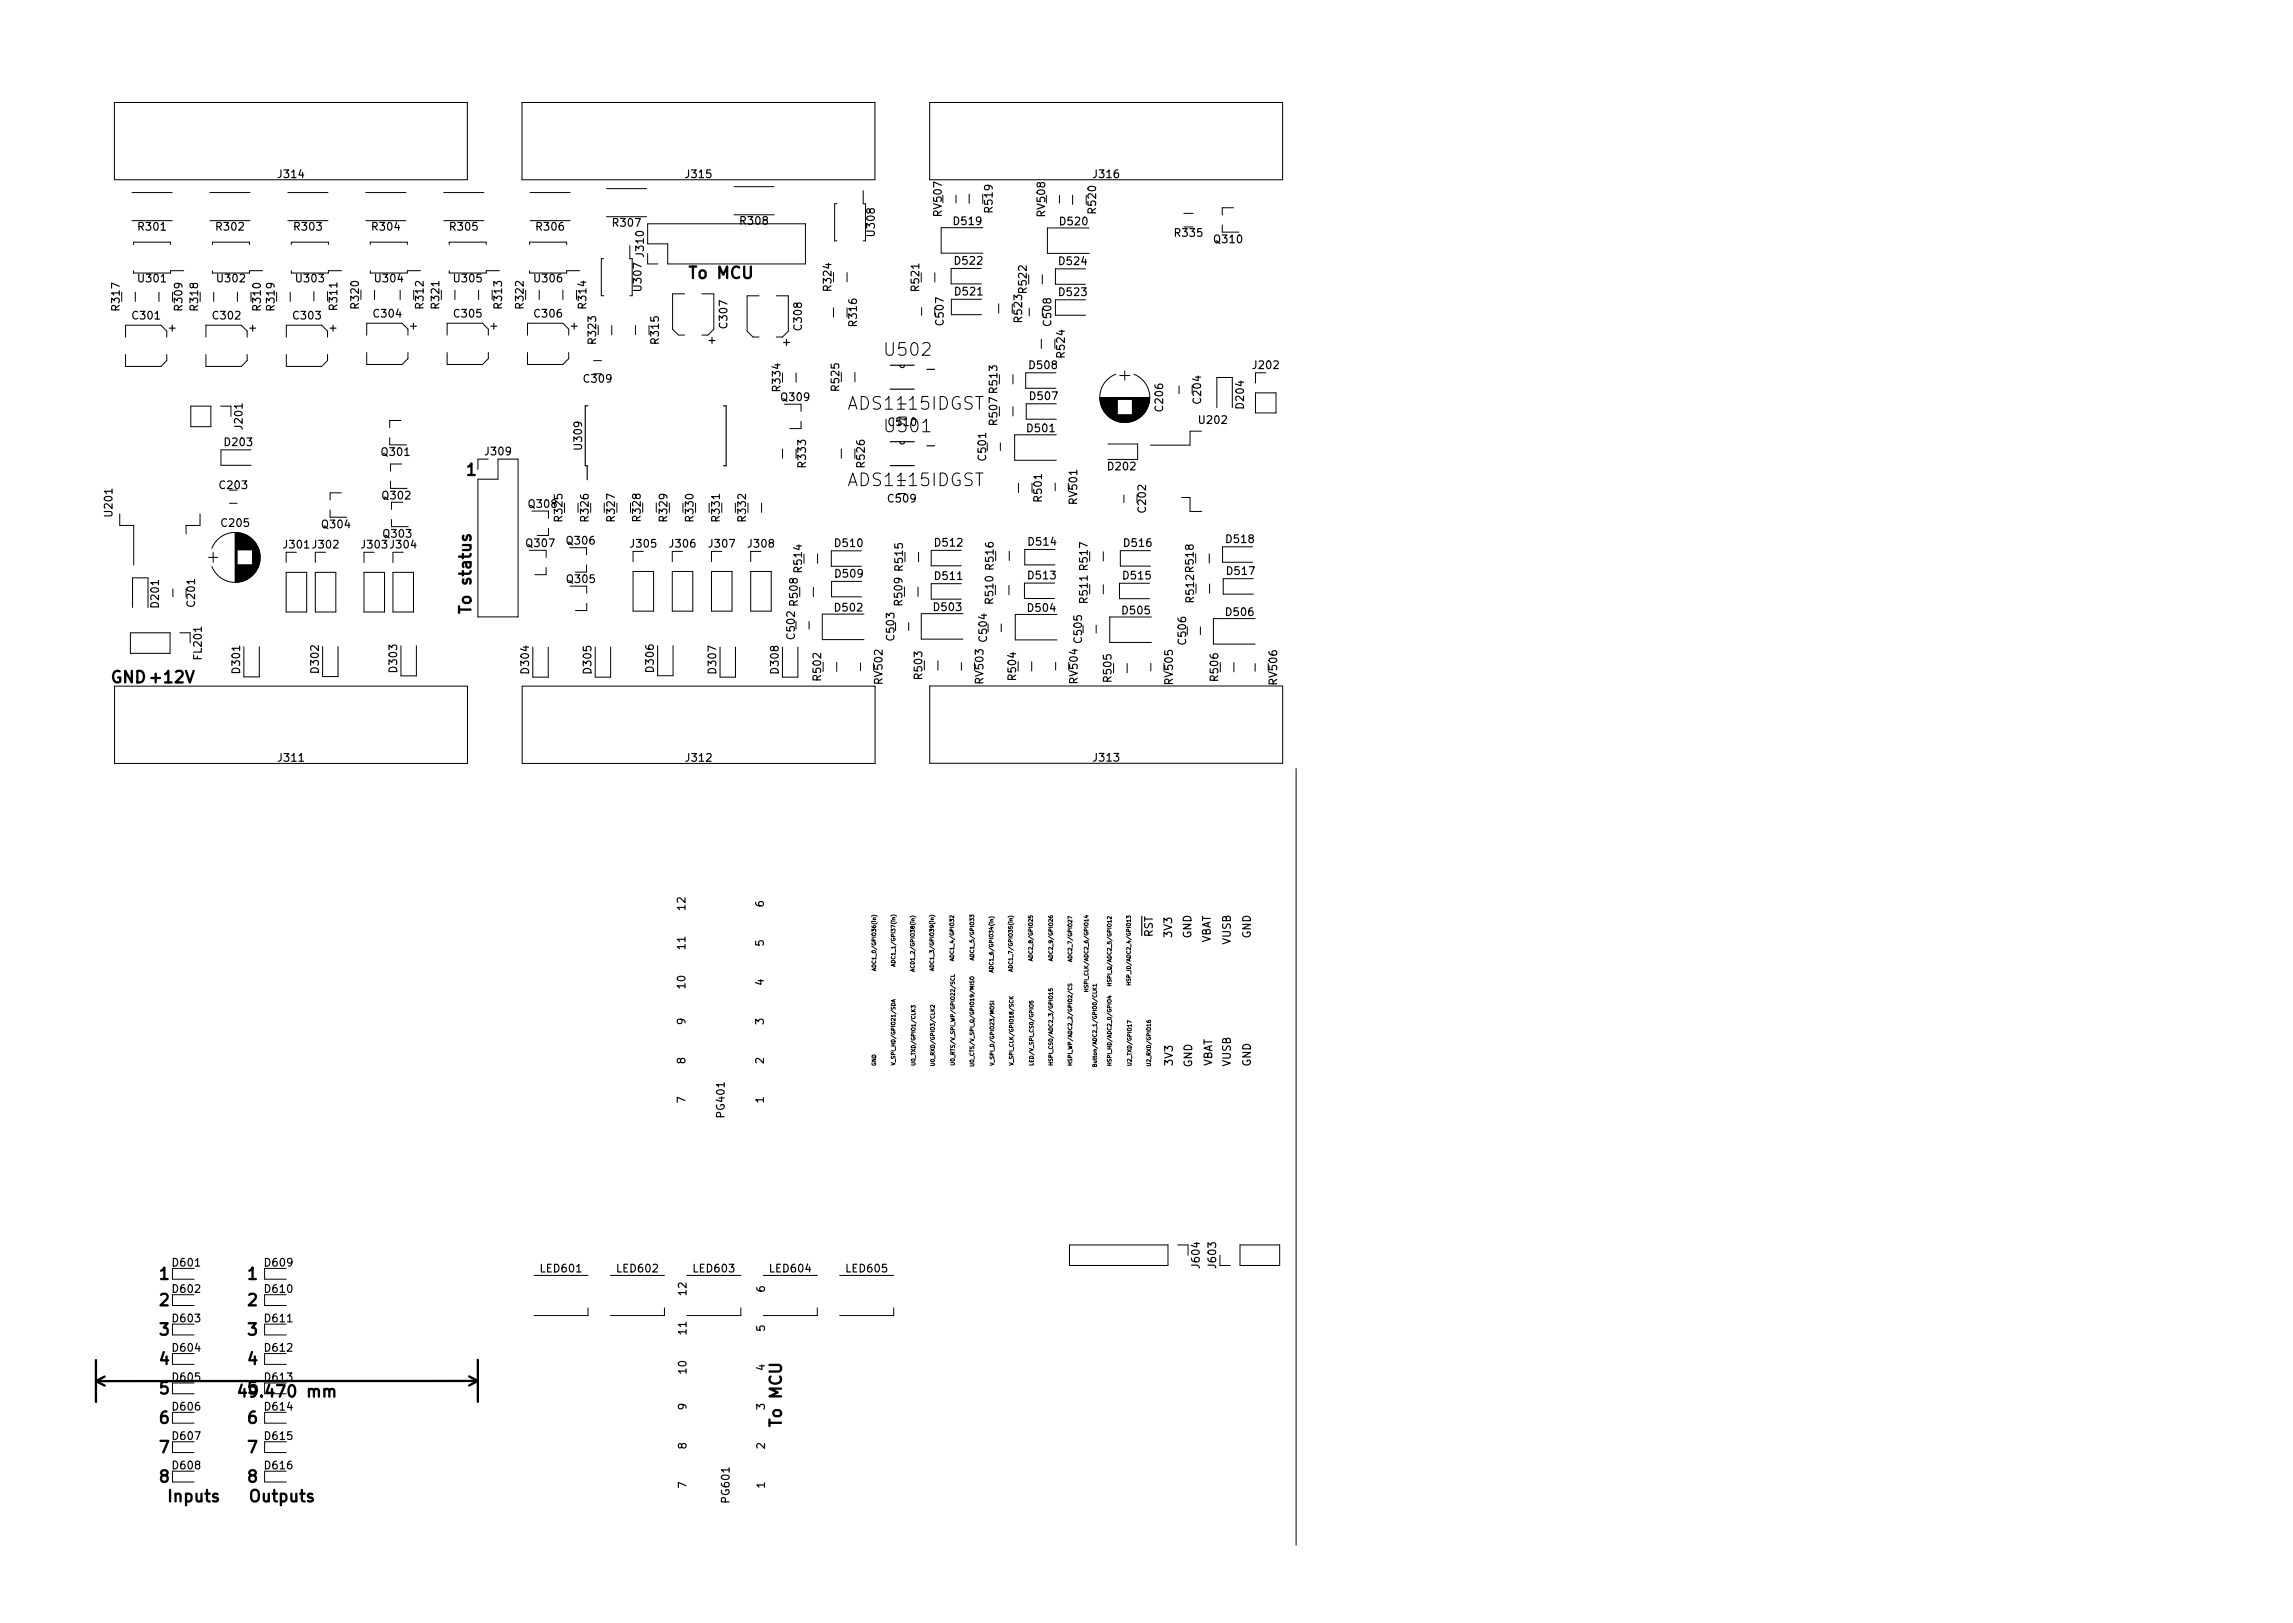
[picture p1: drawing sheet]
<svg xmlns="http://www.w3.org/2000/svg" width="297mm" height="210mm" viewBox="0 0 297 210" stroke-linecap="round" stroke-linejoin="round" font-family="sans-serif">
<defs><g id="words">
<g font-size="2.3">
<text x="114.9" y="46.1">U502</text>
<text x="110.2" y="53.1">ADS1115IDGST</text>
<text x="114.9" y="56">U501</text>
<text x="110.2" y="63">ADS1115IDGST</text>
</g>
<g font-size="2.1">
<text x="89.5" y="36.1">To MCU</text>
<text x="60.5" y="61.6">1</text>
<text x="61" y="78.9" transform="rotate(-90 61 78.9)">To status</text>
<text x="14.3" y="88.5">GND +12V</text>
<text x="20.7" y="165.8">1</text>
<text x="32.1" y="165.8">1</text>
<text x="20.7" y="173">3</text>
<text x="20.7" y="169.2">2</text>
<text x="32.1" y="173">3</text>
<text x="32.1" y="169.2">2</text>
<text x="20.7" y="176.8">4</text>
<text x="32.1" y="176.8">4</text>
<text x="20.7" y="184.4">6</text>
<text x="20.7" y="180.6">5</text>
<text x="31.8" y="181">49.470 mm</text>
<text x="32.1" y="184.4">6</text>
<text x="32.1" y="180.6">5</text>
<text x="101.2" y="184.6" transform="rotate(-90 101.2 184.6)">To MCU</text>
<text x="20.7" y="188.2">7</text>
<text x="32.1" y="188.2">7</text>
<text x="20.7" y="192">8</text>
<text x="22" y="194.6">Inputs</text>
<text x="32.1" y="192">8</text>
<text x="32.5" y="194.6">Outputs</text>
</g>
<g font-size="1.4">
<text x="36.1" y="23.1">J314</text>
<text x="88.9" y="23.1">J315</text>
<text x="141.7" y="23.1">J316</text>
<text x="18" y="29.9">R301</text>
<text x="28.1" y="29.9">R302</text>
<text x="38.2" y="29.9">R303</text>
<text x="48.3" y="29.9">R304</text>
<text x="58.4" y="29.9">R305</text>
<text x="69.6" y="29.9">R306</text>
<text x="79.5" y="29.4">R307</text>
<text x="96" y="29.1">R308</text>
<text x="122" y="27.9" transform="rotate(-90 122 27.9)">RV507</text>
<text x="123.7" y="29.1">D519</text>
<text x="128.6" y="27.4" transform="rotate(-90 128.6 27.4)">R519</text>
<text x="135.4" y="27.9" transform="rotate(-90 135.4 27.9)">RV508</text>
<text x="137.4" y="29.2">D520</text>
<text x="142" y="27.5" transform="rotate(-90 142 27.5)">R520</text>
<text x="83.4" y="33.1" transform="rotate(-90 83.4 33.1)">J310</text>
<text x="113.3" y="30.5" transform="rotate(-90 113.3 30.5)">U308</text>
<text x="123.8" y="34.3">D522</text>
<text x="137.3" y="34.3">D524</text>
<text x="152.3" y="30.7">R335</text>
<text x="157.4" y="31.5">Q310</text>
<text x="15.5" y="40.1" transform="rotate(-90 15.5 40.1)">R317</text>
<text x="17.3" y="41.4">C301</text>
<text x="18" y="36.6">U301</text>
<text x="23.6" y="40.1" transform="rotate(-90 23.6 40.1)">R309</text>
<text x="25.7" y="40.1" transform="rotate(-90 25.7 40.1)">R318</text>
<text x="27.7" y="41.4">C302</text>
<text x="28.3" y="36.6">U302</text>
<text x="33.8" y="40.1" transform="rotate(-90 33.8 40.1)">R310</text>
<text x="35.6" y="40.1" transform="rotate(-90 35.6 40.1)">R319</text>
<text x="38.1" y="41.4">C303</text>
<text x="38.5" y="36.6">U303</text>
<text x="43.7" y="40" transform="rotate(-90 43.7 40)">R311</text>
<text x="46.5" y="39.9" transform="rotate(-90 46.5 39.9)">R320</text>
<text x="48.5" y="41.1">C304</text>
<text x="48.7" y="36.6">U304</text>
<text x="54.9" y="39.9" transform="rotate(-90 54.9 39.9)">R312</text>
<text x="56.9" y="39.9" transform="rotate(-90 56.9 39.9)">R321</text>
<text x="58.9" y="41.1">C305</text>
<text x="58.9" y="36.6">U305</text>
<text x="65" y="39.9" transform="rotate(-90 65 39.9)">R313</text>
<text x="67.8" y="39.9" transform="rotate(-90 67.8 39.9)">R322</text>
<text x="69.3" y="41.1">C306</text>
<text x="69.3" y="36.6">U306</text>
<text x="75.9" y="39.9" transform="rotate(-90 75.9 39.9)">R314</text>
<text x="83.1" y="37.6" transform="rotate(-90 83.1 37.6)">U307</text>
<text x="107.7" y="37.6" transform="rotate(-90 107.7 37.6)">R324</text>
<text x="119.1" y="37.6" transform="rotate(-90 119.1 37.6)">R521</text>
<text x="123.8" y="38.3">D521</text>
<text x="132.4" y="41.6" transform="rotate(-90 132.4 41.6)">R523</text>
<text x="133" y="37.9" transform="rotate(-90 133 37.9)">R522</text>
<text x="137.3" y="38.3">D523</text>
<text x="21.9" y="42.9">+</text>
<text x="32.3" y="42.9">+</text>
<text x="42.7" y="42.9">+</text>
<text x="53.1" y="42.7">+</text>
<text x="63.6" y="42.7">+</text>
<text x="74" y="42.7">+</text>
<text x="77.2" y="44.4" transform="rotate(-90 77.2 44.4)">R323</text>
<text x="85.3" y="44.4" transform="rotate(-90 85.3 44.4)">R315</text>
<text x="92.7" y="44.5" transform="rotate(-90 92.7 44.5)">+</text>
<text x="94.2" y="42.4" transform="rotate(-90 94.2 42.4)">C307</text>
<text x="102.3" y="44.8" transform="rotate(-90 102.3 44.8)">+</text>
<text x="103.9" y="42.7" transform="rotate(-90 103.9 42.7)">C308</text>
<text x="111" y="42.1" transform="rotate(-90 111 42.1)">R316</text>
<text x="122.2" y="42" transform="rotate(-90 122.2 42)">C507</text>
<text x="133.5" y="47.8">D508</text>
<text x="136.2" y="42.1" transform="rotate(-90 136.2 42.1)">C508</text>
<text x="137.9" y="46.2" transform="rotate(-90 137.9 46.2)">R524</text>
<text x="162.4" y="47.8">J202</text>
<text x="75.7" y="49.6">C309</text>
<text x="101.1" y="50.6" transform="rotate(-90 101.1 50.6)">R334</text>
<text x="101.3" y="51.9">Q309</text>
<text x="108.7" y="50.5" transform="rotate(-90 108.7 50.5)">R525</text>
<text x="133.5" y="51.8">D507</text>
<text x="150.7" y="53.2" transform="rotate(-90 150.7 53.2)">C206</text>
<text x="155.6" y="52.2" transform="rotate(-90 155.6 52.2)">C204</text>
<text x="161.1" y="52.8" transform="rotate(-90 161.1 52.8)">D204</text>
<text x="29.2" y="57.8">D203</text>
<text x="31.4" y="55.5" transform="rotate(-90 31.4 55.5)">J201</text>
<text x="49.5" y="59.1">Q301</text>
<text x="63" y="59">J309</text>
<text x="75.4" y="58.1" transform="rotate(-90 75.4 58.1)">U309</text>
<text x="115.2" y="55.2">C510</text>
<text x="127.7" y="59.5" transform="rotate(-90 127.7 59.5)">C501</text>
<text x="129.2" y="55" transform="rotate(-90 129.2 55)">R507 R513</text>
<text x="133.2" y="56">D501</text>
<text x="155.4" y="54.9">U202</text>
<text x="28.6" y="63.3">C203</text>
<text x="49.6" y="64.7">Q302</text>
<text x="68.6" y="65.8">Q308</text>
<text x="104.4" y="60.4" transform="rotate(-90 104.4 60.4)">R333</text>
<text x="112" y="60.4" transform="rotate(-90 112 60.4)">R526</text>
<text x="115.2" y="65.1">C509</text>
<text x="135" y="64.9" transform="rotate(-90 135 64.9)">R501</text>
<text x="139.5" y="65.2" transform="rotate(-90 139.5 65.2)">RV501</text>
<text x="143.6" y="60.9">D202</text>
<text x="14.6" y="66.8" transform="rotate(-90 14.6 66.8)">U201</text>
<text x="28.8" y="68.2">C205</text>
<text x="36.8" y="71">J301 J302</text>
<text x="41.8" y="68.4">Q304</text>
<text x="46.9" y="71">J303 J304</text>
<text x="49.8" y="69.6">Q303</text>
<text x="68.3" y="70.9">Q307</text>
<text x="72.9" y="67.4" transform="rotate(-90 72.9 67.4)">R325</text>
<text x="73.5" y="70.5">Q306</text>
<text x="76.2" y="67.4" transform="rotate(-90 76.2 67.4)">R326</text>
<text x="79.6" y="67.4" transform="rotate(-90 79.6 67.4)">R327</text>
<text x="81.8" y="70.9">J305</text>
<text x="83" y="67.4" transform="rotate(-90 83 67.4)">R328</text>
<text x="86.4" y="67.4" transform="rotate(-90 86.4 67.4)">R329</text>
<text x="86.9" y="70.9">J306</text>
<text x="89.8" y="67.4" transform="rotate(-90 89.8 67.4)">R330</text>
<text x="91.9" y="70.9">J307</text>
<text x="93.2" y="67.4" transform="rotate(-90 93.2 67.4)">R331</text>
<text x="96.6" y="67.4" transform="rotate(-90 96.6 67.4)">R332</text>
<text x="97" y="70.9">J308</text>
<text x="108.3" y="70.9">D510</text>
<text x="121.2" y="70.8">D512</text>
<text x="133.3" y="70.7">D514</text>
<text x="145.7" y="70.8">D516</text>
<text x="148.4" y="66.3" transform="rotate(-90 148.4 66.3)">C202</text>
<text x="159" y="70.3">D518</text>
<text x="73.5" y="75.5">Q305</text>
<text x="103.9" y="74" transform="rotate(-90 103.9 74)">R514</text>
<text x="108.3" y="74.8">D509</text>
<text x="117" y="73.8" transform="rotate(-90 117 73.8)">R515</text>
<text x="121.2" y="75.1">D511</text>
<text x="128.7" y="73.7" transform="rotate(-90 128.7 73.7)">R516</text>
<text x="133.3" y="75">D513</text>
<text x="145.6" y="75.1">D515</text>
<text x="154.7" y="77.9" transform="rotate(-90 154.7 77.9)">R512 R518</text>
<text x="159" y="74.5">D517</text>
<text x="20.6" y="78.6" transform="rotate(-90 20.6 78.6)">D201</text>
<text x="25.3" y="78.5" transform="rotate(-90 25.3 78.5)">C201</text>
<text x="103" y="82.7" transform="rotate(-90 103 82.7)">C502</text>
<text x="103.3" y="78.4" transform="rotate(-90 103.3 78.4)">R508</text>
<text x="108.3" y="79.2">D502</text>
<text x="115.9" y="82.8" transform="rotate(-90 115.9 82.8)">C503</text>
<text x="116.9" y="78.3" transform="rotate(-90 116.9 78.3)">R509</text>
<text x="121.1" y="79.1">D503</text>
<text x="127.8" y="83" transform="rotate(-90 127.8 83)">C504</text>
<text x="128.7" y="78.1" transform="rotate(-90 128.7 78.1)">R510</text>
<text x="133.3" y="79.2">D504</text>
<text x="140.2" y="83.2" transform="rotate(-90 140.2 83.2)">C505</text>
<text x="140.9" y="78" transform="rotate(-90 140.9 78)">R511 R517</text>
<text x="145.5" y="79.6">D505</text>
<text x="153.6" y="83.4" transform="rotate(-90 153.6 83.4)">C506</text>
<text x="158.9" y="79.8">D506</text>
<text x="26.1" y="85.3" transform="rotate(-90 26.1 85.3)">FL201</text>
<text x="31.1" y="87.1" transform="rotate(-90 31.1 87.1)">D301</text>
<text x="41.3" y="87.1" transform="rotate(-90 41.3 87.1)">D302</text>
<text x="51.4" y="87" transform="rotate(-90 51.4 87)">D303</text>
<text x="68.5" y="87.1" transform="rotate(-90 68.5 87.1)">D304</text>
<text x="76.6" y="87.1" transform="rotate(-90 76.6 87.1)">D305</text>
<text x="84.7" y="87" transform="rotate(-90 84.7 87)">D306</text>
<text x="92.8" y="87.1" transform="rotate(-90 92.8 87.1)">D307</text>
<text x="100.9" y="87.1" transform="rotate(-90 100.9 87.1)">D308</text>
<text x="106.4" y="88.1" transform="rotate(-90 106.4 88.1)">R502</text>
<text x="114.3" y="88.5" transform="rotate(-90 114.3 88.5)">RV502</text>
<text x="119.5" y="87.9" transform="rotate(-90 119.5 87.9)">R503</text>
<text x="127.4" y="88.5" transform="rotate(-90 127.4 88.5)">RV503</text>
<text x="131.6" y="88" transform="rotate(-90 131.6 88)">R504</text>
<text x="139.6" y="88.4" transform="rotate(-90 139.6 88.4)">RV504</text>
<text x="144" y="88.2" transform="rotate(-90 144 88.2)">R505</text>
<text x="151.9" y="88.6" transform="rotate(-90 151.9 88.6)">RV505</text>
<text x="157.8" y="88.1" transform="rotate(-90 157.8 88.1)">R506</text>
<text x="165.4" y="88.6" transform="rotate(-90 165.4 88.6)">RV506</text>
<text x="36.2" y="98.7">J311</text>
<text x="89" y="98.7">J312</text>
<text x="141.8" y="98.6">J313</text>
<text x="88.8" y="117.9" transform="rotate(-90 88.8 117.9)">12</text>
<text x="98.9" y="117.5" transform="rotate(-90 98.9 117.5)">6</text>
<text x="88.8" y="122.9" transform="rotate(-90 88.8 122.9)">11</text>
<text x="98.9" y="122.5" transform="rotate(-90 98.9 122.5)">5</text>
<text x="149.3" y="121.4" transform="rotate(-90 149.3 121.4)">RST</text>
<text x="151.8" y="121.4" transform="rotate(-90 151.8 121.4)">3V3</text>
<text x="154.3" y="121.6" transform="rotate(-90 154.3 121.6)">GND</text>
<text x="156.8" y="122.2" transform="rotate(-90 156.8 122.2)">VBAT</text>
<text x="159.4" y="122.4" transform="rotate(-90 159.4 122.4)">VUSB</text>
<text x="162" y="121.6" transform="rotate(-90 162 121.6)">GND</text>
<text x="88.8" y="128" transform="rotate(-90 88.8 128)">10</text>
<text x="98.9" y="127.6" transform="rotate(-90 98.9 127.6)">4</text>
<text x="88.8" y="137.8" transform="rotate(-90 88.8 137.8)">8</text>
<text x="88.8" y="132.7" transform="rotate(-90 88.8 132.7)">9</text>
<text x="98.9" y="137.8" transform="rotate(-90 98.9 137.8)">2</text>
<text x="98.9" y="132.7" transform="rotate(-90 98.9 132.7)">3</text>
<text x="151.9" y="138" transform="rotate(-90 151.9 138)">3V3</text>
<text x="88.8" y="142.9" transform="rotate(-90 88.8 142.9)">7</text>
<text x="98.9" y="142.9" transform="rotate(-90 98.9 142.9)">1</text>
<text x="154.4" y="138.3" transform="rotate(-90 154.4 138.3)">GND</text>
<text x="157" y="138.2" transform="rotate(-90 157 138.2)">VBAT</text>
<text x="159.4" y="138.2" transform="rotate(-90 159.4 138.2)">VUSB</text>
<text x="162" y="138.2" transform="rotate(-90 162 138.2)">GND</text>
<text x="93.9" y="144.6" transform="rotate(-90 93.9 144.6)">PG401</text>
<text x="22.5" y="167.5">D602</text>
<text x="22.5" y="164.1">D601</text>
<text x="34.4" y="167.5">D610</text>
<text x="34.4" y="164.1">D609</text>
<text x="70.1" y="164.8">LED601</text>
<text x="80" y="164.8">LED602</text>
<text x="88.9" y="167.8" transform="rotate(-90 88.9 167.8)">12</text>
<text x="89.9" y="164.8">LED603</text>
<text x="99.1" y="167.4" transform="rotate(-90 99.1 167.4)">6</text>
<text x="99.8" y="164.8">LED604</text>
<text x="109.7" y="164.8">LED605</text>
<text x="155.4" y="164.2" transform="rotate(-90 155.4 164.2)">J604</text>
<text x="157.5" y="164.2" transform="rotate(-90 157.5 164.2)">J603</text>
<text x="22.5" y="171.3">D603</text>
<text x="34.4" y="171.3">D611</text>
<text x="88.9" y="172.8" transform="rotate(-90 88.9 172.8)">11</text>
<text x="99.1" y="172.4" transform="rotate(-90 99.1 172.4)">5</text>
<text x="22.5" y="178.9">D605</text>
<text x="22.5" y="175.1">D604</text>
<text x="34.4" y="178.9">D613</text>
<text x="34.4" y="175.1">D612</text>
<text x="88.9" y="177.9" transform="rotate(-90 88.9 177.9)">10</text>
<text x="99.1" y="177.5" transform="rotate(-90 99.1 177.5)">4</text>
<text x="22.5" y="182.7">D606</text>
<text x="34.4" y="182.7">D614</text>
<text x="88.9" y="182.6" transform="rotate(-90 88.9 182.6)">9</text>
<text x="99.1" y="182.6" transform="rotate(-90 99.1 182.6)">3</text>
<text x="22.5" y="190.3">D608</text>
<text x="22.5" y="186.5">D607</text>
<text x="34.4" y="190.3">D616</text>
<text x="34.4" y="186.5">D615</text>
<text x="88.9" y="187.7" transform="rotate(-90 88.9 187.7)">8</text>
<text x="99.1" y="187.7" transform="rotate(-90 99.1 187.7)">2</text>
<text x="88.9" y="192.8" transform="rotate(-90 88.9 192.8)">7</text>
<text x="94.5" y="194.5" transform="rotate(-90 94.5 194.5)">PG601</text>
<text x="99.1" y="192.8" transform="rotate(-90 99.1 192.8)">1</text>
</g>
<g font-size=".7">
<text x="113.5" y="125.4" transform="rotate(-90 113.5 125.4)">ADC1_0/GPIO36(in)</text>
<text x="116" y="124.8" transform="rotate(-90 116 124.8)">ADC1_1/GPI37(in)</text>
<text x="118.5" y="125.5" transform="rotate(-90 118.5 125.5)">ACD1_2/GPIO38(in)</text>
<text x="121" y="125.4" transform="rotate(-90 121 125.4)">ADC1_3/GPIO39(in)</text>
<text x="123.6" y="124.2" transform="rotate(-90 123.6 124.2)">ADC1_4/GPIO32</text>
<text x="126.2" y="124.1" transform="rotate(-90 126.2 124.1)">ADC1_5/GPIO33</text>
<text x="128.7" y="125.6" transform="rotate(-90 128.7 125.6)">ADC1_6/GPIO34(in)</text>
<text x="131.2" y="125.5" transform="rotate(-90 131.2 125.5)">ADC1_7/GPIO35(in)</text>
<text x="133.8" y="124.2" transform="rotate(-90 133.8 124.2)">ADC2_8/GPIO25</text>
<text x="136.4" y="124.2" transform="rotate(-90 136.4 124.2)">ADC2_9/GPIO26</text>
<text x="138.9" y="124.3" transform="rotate(-90 138.9 124.3)">ADC2_7/GPIO27</text>
<text x="141" y="128" transform="rotate(-90 141 128)">HSPI_CLK/ADC2_6/GPIO14</text>
<text x="144" y="127.3" transform="rotate(-90 144 127.3)">HSPI_Q/ADC2_5/GPIO12</text>
<text x="146.5" y="127.2" transform="rotate(-90 146.5 127.2)">HSP_ID/ADC2_4/GPIO13</text>
<text x="116" y="137.6" transform="rotate(-90 116 137.6)">V_SPI_HD/GPIO21/SDA</text>
<text x="118.6" y="137.6" transform="rotate(-90 118.6 137.6)">U0_TXD/GPIO1/CLK3</text>
<text x="121.1" y="137.7" transform="rotate(-90 121.1 137.7)">U0_RXD/GPIO3/CLK2</text>
<text x="123.7" y="137.5" transform="rotate(-90 123.7 137.5)">U0_RTS/V_SPI_WP/GPIO22/SCL</text>
<text x="126.2" y="137.6" transform="rotate(-90 126.2 137.6)">U0_CTS/V_SPI_Q/GPIO19/MISO</text>
<text x="128.8" y="137.6" transform="rotate(-90 128.8 137.6)">V_SPI_D/GPIO23/MOSI</text>
<text x="131.3" y="137.6" transform="rotate(-90 131.3 137.6)">V_SPI_CLK/GPIO18/SCK</text>
<text x="133.9" y="137.6" transform="rotate(-90 133.9 137.6)">LED/V_SPI_CS0/GPIO5</text>
<text x="136.4" y="137.5" transform="rotate(-90 136.4 137.5)">HSPI_CS0/ADC2_3/GPIO15</text>
<text x="138.9" y="137.5" transform="rotate(-90 138.9 137.5)">HSPI_WP/ADC2_2/GPIO2/CS</text>
<text x="142.1" y="137.6" transform="rotate(-90 142.1 137.6)">Button/ADC2_1/GPIO0/CLK1</text>
<text x="144" y="137.6" transform="rotate(-90 144 137.6)">HSPI_HD/ADC2_0/GPIO4</text>
<text x="146.6" y="137.8" transform="rotate(-90 146.6 137.8)">U2_TXD/GPIO17</text>
<text x="149.1" y="137.9" transform="rotate(-90 149.1 137.9)">U2_RXD/GPIO16</text>
<text x="113.5" y="138.1" transform="rotate(-90 113.5 138.1)">GND</text>
</g>
</g></defs>
<path d="M12.4 176.2v5.4M12.4 178.9l1.2 .6M13.6 178.3l-1.2 .6M31.3 179.4l-.3 1h.9M60.8 178.3l1.1 .6M61.9 176.2v5.4M61.9 178.9h-49.5M61.9 178.9l-1.1 .6M42.7 180.1l.2-.2 .3 .1 .1 .9" fill="none" stroke="#000" stroke-width=".3"/>
<g fill="none" stroke="#000" stroke-width=".13">
<path d="M14.8 13.3h45.7v10h-45.7zM67.6 13.3h45.7v10h-45.7zM120.4 13.3h45.8v10h-45.8zM17.1 24.9h5.2M17.1 28.6h5.2M17.3 35.1v.3h4.8v-.3h1.7M17.3 31.7v-.3h4.8v.3M17.5 37.9v1.2M20.6 37.9v1.2M27.2 24.9h5.2M27.2 28.6h5.2M27.5 35.1v.3h4.8v-.3h1.7"/>
<path d="M27.5 31.7v-.3h4.8v.3M27.7 37.9v1.2M30.8 37.9v1.2M37.3 24.9h5.2M37.3 28.6h5.2M37.6 37.9v1.2M37.7 35.1v.3h4.8v-.3h1.7M37.7 31.7v-.3h4.8v.3M40.7 37.8v1.2M47.4 24.9h5.2M47.4 28.6h5.2M48 35.1v.3h4.8v-.3h1.7"/>
<path d="M48 31.7v-.3h4.8v.3M48.5 37.6v1.2M51.8 37.6v1.2M57.5 24.9h5.2M57.5 28.6h5.2M58.2 35.1v.3h4.8v-.3h1.7M58.2 31.7v-.3h4.8v.3M58.9 37.6v1.2M62 37.6v1.2M68.6 35.1v.3h4.8v-.3h1.7M68.6 31.7v-.3h4.8v.3M68.7 24.9h5.2"/>
<path d="M68.7 28.6h5.2M69.9 37.6v1.2M72.9 37.6v1.2M78.2 33.5h-.3v4.8h.3M78.6 28.1h5.2M78.6 24.4h5.2M81.6 31.8v1.7h.3v4.8h-.3M83.9 29h20.4v5.2h-17.8v-2.6h-2.6zM83.9 32.9v1.3h1.3M88.7 38.1h-1.6v4.5l.8 .8h.8M90.9 38.1h1.6v4.5l-.8 .8h-.8M95.1 24.2h5.2"/>
<path d="M95.1 27.8h5.2M98.3 38.3h-1.5v4.6l.7 .8h.8M100.6 38.3h1.5v4.6l-.7 .8h-.8M108 39.9v1.2M108.4 26.4h-.3v4.8h.3M109.7 35.3v1.2M111.8 24.7v1.7h.3v4.8h-.3M119.4 39.8v1M121.1 35.3v1.2M123.8 25.3v1M125.5 25.1v1.2M127.1 34.8h-3.9v2h3.9"/>
<path d="M127.1 38.8h-3.9v2h3.9M127.3 29.5h-5.4v3.3h5.4M129.4 39.4v1.2M133.3 39.9v1M135 35.6v1.2M137.2 25.3v1M138.9 25.3v1.2M140.6 34.8h-3.9v2h3.9M140.6 38.8h-3.9v2h3.9M141.1 29.5h-5.4v3.3h5.4M153.4 27.6h1.2M158.3 29.1v1"/>
<path d="M159.8 26.9h-1.5v.9M16.3 43.7v-1.6h4.5l.8 .8v.8M16.3 45.9v1.6h4.5l.8-.8v-.8M24.7 52.6h2.6v2.7h-2.6zM26.7 43.7v-1.6h4.6l.7 .8v.8M26.7 45.9v1.6h4.6l.7-.8v-.8M28.6 52.6h1.3v1.3M32.5 58.3h-3.9v2h3.9M37.1 43.7v-1.6h4.6l.7 .8v.8M37.1 45.9v1.6h4.6l.7-.8v-.8M47.5 45.7v1.5h4.6l.7-.7v-.8M47.5 43.4v-1.5h4.6l.7 .7v.8"/>
<path d="M50.5 56.7v.9M51.9 54.5h-1.4v.9M57.9 45.7v1.5h4.6l.8-.7v-.8M57.9 43.4v-1.5h4.6l.8 .7v.8M61.9 59.5h1.3M64.5 59.5h2.6v20.4h-5.2v-17.8h2.6zM68.3 43.4v-1.5h4.6l.8 .7v.8M68.3 45.7v1.5h4.6l.8-.7v-.8M76.9 46.7h1M79.3 42.2v1.2M82.3 42.2v1.2M101.4 58.2v1.2"/>
<path d="M103.1 48.3v1.2M103.8 54.6v.9h-1.5M103.8 52.4v.9M109 58.2v1.2M110.7 48.3v1.2M129.6 57.4v1M131.2 48.5v1.2M131.2 52.7v1.2M134.9 43.9v1.2M136.8 48.3h-3.9v2h3.9M136.8 56.3h-5.4v3.3h5.4M136.8 52.3h-3.9v2h3.9"/>
<path d="M142.5 51.5h6.4M142.5 51.6h6.4M142.5 51.7h6.4M142.5 51.8h2.2M142.5 51.9h2.2M142.5 52h2.2M142.6 52.1h2.1M142.6 52.2h2.1M142.6 52.3h2.1M142.6 52.4h2.1M142.6 52.5h2.1M142.7 52.5h2"/>
<path d="M142.7 52.6h2M142.7 52.7h2M142.8 52.7h1.9M142.8 52.8h1.9M142.8 52.9h1.9M142.9 53h1.8M142.9 53.1h1.8M143 53.2h1.7M143 53.3h1.7M143.1 53.3h1.6M143.1 53.4h1.6M143.2 53.5h1.5"/>
<path d="M143.3 53.6h1.4M143.3 53.7h1.4M143.4 53.7h1.3M143.4 53.7h4.6M143.4 53.8h4.6M143.5 53.8h4.4M143.5 57.5h3.9v2h-3.9M143.5 53.9h4.4M143.6 53.9h4.2M143.7 54h4M143.8 54.1h3.8M143.9 54.1h3.6"/>
<path d="M143.9 54.2h3.6M144 54.2h3.4M144 54.3h3.4M144.1 54.3h3.2M144.2 54.3h3M144.3 54.4h2.8M144.4 54.5h2.6M144.5 54.5h2.4M144.5 48.5a3.2 3.2 0 0 0-2 3 3.2 3.2 0 0 0 2 3M144.6 54.5h2.2M144.7 54.6h2M144.9 54.6h1.6"/>
<path d="M145 54.7h1.4M145.1 48.6h1.3M145.2 54.7h1M145.7 48v1.2M146.7 52.3h2.1M146.7 53.5h1.5M146.7 52.6h2M146.7 51.8h2.2M146.7 51.9h2.2M146.7 52h2.2M146.7 52.1h2.2M146.7 52.1h2.1"/>
<path d="M146.7 52.2h2.1M146.7 52.4h2.1M146.7 52.5h2.1M146.7 52.5h2M146.7 52.7h2M146.7 52.8h1.9M146.7 52.9h1.9M146.7 53h1.8M146.7 53.1h1.8M146.7 53.2h1.7M146.7 53.3h1.7M146.7 53.3h1.6"/>
<path d="M146.7 53.4h1.6M146.7 53.6h1.4M146.7 53.7h1.4M146.7 53.7h1.3M146.9 48.5a3.2 3.2 0 0 1 1.8 4.2 3.2 3.2 0 0 1-4.2 1.8M152.7 50v1M155.7 55.9h-1.5v1.8h-5.2M157.6 52.8v-3.9h2v3.9M162.6 48.3v1.3M162.6 50.9h2.7v2.6h-2.7zM15.5 66.6v1.5h1.8v5.1M17.2 78.7v-3.8h2v3.8"/>
<path d="M22.4 76.3v1M25.9 66.6v1.5h-1.8v1.1M27 72.2h1.2M27.4 71a3.2 3.2 0 0 1 5-1.4 3.2 3.2 0 0 1 0 5.2 3.2 3.2 0 0 1-5-1.4M27.6 71.6v1.3M29.7 65.2h1M30.5 69v6.4M30.6 69v6.4M30.7 69v6.4M30.7 69v2.2M30.7 73.2v2.2M30.8 69v2.2"/>
<path d="M30.8 73.2v2.2M30.9 69v2.2M30.9 73.2v2.2M31 69.1v2.1M31 73.2v2.2M31.1 69.1v2.1M31.1 73.2v2.2M31.1 73.2v2.1M31.2 69.1v2.1M31.2 73.2v2.1M31.3 69.1v2.1M31.3 73.2v2.1"/>
<path d="M31.4 69.1v2.1M31.4 73.2v2.1M31.4 69.2v2M31.5 69.2v2M31.5 73.2v2.1M31.5 73.2v2M31.6 69.2v2M31.6 73.2v2M31.7 69.2v2M31.7 73.2v2M31.7 69.3v1.9M31.7 73.2v1.9"/>
<path d="M31.8 69.3v1.9M31.8 73.2v1.9M31.9 69.3v1.9M31.9 73.2v1.9M31.9 69.4v1.8M32 69.4v1.8M32 73.2v1.8M32.1 69.4v1.8M32.1 73.2v1.8M32.1 69.5v1.7M32.1 73.2v1.7M32.2 69.5v1.7"/>
<path d="M32.2 73.2v1.7M32.3 69.6v1.6M32.3 73.2v1.7M32.3 73.2v1.6M32.4 69.6v1.6M32.4 73.2v1.6M32.4 69.7v1.5M32.4 73.2v1.5M32.5 69.7v1.5M32.5 73.2v1.5M32.5 69.8v1.4M32.6 69.8v1.4"/>
<path d="M32.6 73.2v1.4M32.7 69.9v1.3M32.7 73.2v1.3M32.7 69.9v4.6M32.8 70v4.4M32.9 70.1v4.2M32.9 70.2v4.1M33 70.2v4M33 70.3v3.9M33.1 70.3v3.8M33.1 70.4v3.6M33.2 70.5v3.4"/>
<path d="M33.2 70.6v3.3M33.3 70.6v3.2M33.3 70.7v3M33.3 70.8v2.9M33.4 70.8v2.8M33.4 70.9v2.6M33.5 71v2.4M33.5 71.1v2.2M33.5 71.2v2M33.6 71.4v1.6M33.6 71.5v1.4M33.7 71.7v1"/>
<path d="M37.1 71.5v1.4M37.1 74.1h2.6v5.2h-2.6zM40.8 74.1h2.7v5.2h-2.7zM40.8 71.5v1.4M42.8 66.1v.9M44.2 63.8h-1.4v1M47.2 74.1h2.6v5.2h-2.6zM47.2 71.5v1.4M50.6 62.3v1M50.7 65.1v.9M50.7 67.3v.9M50.9 74.1h2.7v5.2h-2.7z"/>
<path d="M50.9 71.5v1.4M52 60.1h-1.4v.9M70.7 71.3v.9M70.7 73.5v.9h-1.4M71.1 66.2v.9M71.1 68.4v1h-1.5M76 71v.9M76 73.2v.9M76 78.2v.9h-1.5M76 75.9v1M82 74h2.7v5.2h-2.7zM82 71.4v1.4"/>
<path d="M87.1 74h2.6v5.2h-2.6zM87.1 71.4v1.4M92.2 74h2.6v5.2h-2.6zM92.2 71.4v1.4M97.2 71.4v1.4M97.2 74h2.7v5.2h-2.7zM98.7 65.2v1.2M105.4 76.1v1.2M105.9 71.8v1.2M111.6 71.4h-3.9v2h3.9M111.6 75.3h-3.9v2h3.9M111.9 79.6h-5.4v3.3h5.4"/>
<path d="M118.9 76.1v1.2M119 71.6v1.2M124.5 75.6h-3.9v2h3.9M124.5 71.3h-3.9v2h3.9M124.7 79.5h-5.4v3.3h5.4M130.7 75.8v1.2M130.7 71.4v1.2M131.9 62.6v1.2M136.6 75.5h-3.9v2h3.9M136.6 71.2h-3.8v2h3.8M136.7 62.6v1M136.9 79.6h-5.4v3.3h5.4"/>
<path d="M142.9 71.5v1.2M142.9 75.7v1.2M145.6 64.1v1M148.9 75.6h-3.9v2h3.9M149 71.3h-3.9v2h3.9M149.2 79.9h-5.4v3.3h5.4M153.1 64.4h1.1v1.9h1.5M156.6 71.7v1.2M156.7 75.7v1.2M162.3 70.8h-3.9v2h3.9M162.4 75h-3.9v2h3.9M14.8 88.9h45.8v10h-45.8z"/>
<path d="M16.9 82h5.1v2.6h-5.1zM23.3 82h1.3v1.3M31.6 83.8v3.9h2v-3.9M41.8 83.7v3.9h2v-3.9M51.9 83.7v3.9h2v-3.9M67.6 88.9h45.8v10h-45.8zM69 83.8v3.9h2v-3.9M77.1 83.8v3.9h2v-3.9M85.2 83.6v3.9h2v-3.9M93.3 83.8v3.9h2v-3.9M101.4 83.8v3.9h2v-3.9M104.8 80.5v1"/>
<path d="M108.4 85.8v1.2M111.5 85.9v1M117.7 80.7v1M120.4 88.9h45.8v10h-45.8zM121.5 85.6v1.2M124.5 85.8v1M129.7 80.8v1M133.6 85.7v1.2M136.8 85.8v1M142 81v1M146 86v1.2M149.1 85.9v1"/>
<path d="M155.5 81.2v1M159.8 85.8v1.2M162.6 86v1M162.6 80.1h-5.4v3.3h5.4M167.9 99.6v100.6M112.9 118.7l.3-.1 .4 .1M115.4 118.7l.3-.2 .4 .2M117.9 118.8l.3-.1 .4 .1M120.4 118.7l.3-.1 .4 .1M123.6 118.6v.3l-.4-.3-.1 .1v.2M128.1 118.9l.3-.1 .4 .1M130.6 118.8l.3-.1 .4 .1"/>
<path d="M138.9 118.9l-.5-.2v.3M140.6 118.7h.4M140.8 118.6v.3l-.4-.1M144 118.7v.4l-.4-.4-.1 .1v.2M146 119v-.3l.1 .1 .1-.1h.2v.3M113.3 125.5v.2M113.5 125.4l-.5 .2 .5 .2M115.5 137.7l.5 .1-.5 .2M115.8 124.9v.3M115.8 129.5v.3M116 129.5l-.5 .2 .5 .1M116 124.9l-.5 .1 .5 .2"/>
<path d="M118.1 137.7h.4l.1 .1-.1 .2h-.4M118.1 130.6v-.3l.1 .1 .1-.1h.2v.3M118.3 125.6v.2M118.5 125.5l-.5 .2 .5 .2M120.6 137.7h.4l.1 .1-.1 .2h-.4M120.8 125.5v.2M121 125.4l-.5 .2 .5 .2M121.1 130.2v.3l-.4-.3-.1 .1v.2M123.2 137.7h.4l.1 .1-.1 .2h-.4M123.6 124.2l-.5 .1 .5 .2M123.7 126.2v.3h-.5M125.7 137.8h.4l.1 .1-.1 .2h-.4"/>
<path d="M125.7 126.6h.4l.1 .2-.2 .1h-.3zM126.2 124.1l-.5 .1 .5 .2M128.3 137.7l.5 .2-.5 .1M128.3 129.7h.5M128.5 125.7v.2M128.7 125.6l-.5 .2 .5 .2M130.8 137.7l.5 .1-.5 .2M130.8 129.1l.2 .3M131 125.6v.2M131.2 125.5l-.5 .2 .5 .2M131.3 129.1l-.3 .2M133.4 129.7v.2l.2 .1v-.3h.2v.3"/>
<path d="M133.8 124.2l-.5 .1 .5 .2M133.9 137.7v.3h-.5M135.9 128.1v.2l.2 .1v-.3h.2v.3M135.9 138h.5M136.1 137.7v.3M136.4 124.2l-.5 .1 .5 .2M138.4 138h.5M138.4 137.7h.5M138.4 127.5v.2a.21 .21 0 0 0 .3-.2h.1v.2M138.6 137.7v.3M138.9 124.3l-.5 .1 .5 .2M140.5 128.4h.5"/>
<path d="M140.7 128.2v.2M141.6 128l.2 .3M141.8 138l.1-.1 .2 .1v.2h-.5v-.3h.2v.3M142.1 127.6h-.5l.1 .2M142.1 128l-.3 .2M142.1 127.5v.3M143.5 138h.5M143.5 127.7h.5M143.6 129.1h.4M143.7 127.4v.3M143.7 137.7v.3M143.8 129v.3l-.4-.1"/>
<path d="M146 127.6h.5M146.2 127.3v.3M146.6 132.4l-.5-.2v.4M148.6 137.8h.4l.1 .1-.1 .2h-.4M148.6 132.2l.1 .2 .3 .1 .1-.1-.1-.2h-.2v.3M22.3 176.7h2.8M22.3 175.3h2.8M22.3 171.5h2.8M22.3 172.9h2.8M22.3 169.1h2.8M22.3 167.7h2.8M22.3 179.2h2.8"/>
<path d="M25.1 164.3h-2.8v1.4h2.8M37.1 164.3h-2.8v1.4h2.8M37.1 167.7h-2.8v1.4h2.8M37.1 171.5h-2.8v1.4h2.8M37.1 175.3h-2.8v1.4h2.8M69.2 165.2h7M76.2 169.4v1h-7M79.1 165.2h7M86.1 169.4v1h-7M89 165.2h7M96 169.4v1h-7M98.9 165.2h7"/>
<path d="M105.9 169.4v1h-7M108.8 165.2h7M115.8 169.4v1h-7M138.5 161.3h12.8v2.6h-12.8zM152.6 161.3h1.3v1.3M158 163.9h1.4M160.6 161.3h5.2v2.6h-5.2zM22.3 192h2.8M22.3 190.6h2.8M22.3 184.4h2.8M22.3 183h2.8M22.3 180.6h2.8"/>
<path d="M22.3 186.8h2.8M22.3 188.2h2.8M37.1 190.6h-2.8v1.4h2.8M37.1 183h-2.8v1.4h2.8M37.1 186.8h-2.8v1.4h2.8"/>
</g>
<path d="M76.2 52.6h-.4v7.7h.3v1.9M93.7 52.6h.4v7.7h-.4M115.3 47.3h3.1M115.3 50.4h3.1M115.3 57.2h3.1M116.6 47.3l.1 .2 .2 .1 .2-.1 .1-.2M116.6 57.2l.1 .2 .2 .1 .2-.1 .1-.2M120.1 47.8h1M120.1 57.8h1M115.3 60.3h3.1" fill="none" stroke="#000" stroke-width=".15"/>
<use href="#words"/>
</svg>
